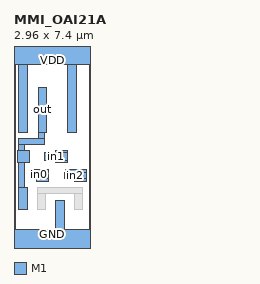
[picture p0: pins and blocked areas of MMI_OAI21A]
MACRO MMI_OAI21A
	CLASS CORE ;
	FOREIGN MMI_OAI21A 0 0 ;
	SIZE 2.96 BY 7.4 ;
	SYMMETRY X Y ;
	SITE CORE1 ;
	PIN out
		DIRECTION output ;
		USE SIGNAL ;
		PORT
			LAYER M1 ;
			RECT 0.94 4.275 1.28 6.035 ;
			LAYER M1 ;
			RECT 0.94 4.02 1.17 4.275 ;
			LAYER M1 ;
			RECT 0.18 3.79 1.17 4.02 ;
			LAYER M1 ;
			RECT 0.18 3.555 0.41 3.79 ;
			LAYER M1 ;
			RECT 0.145 3.105 0.595 3.555 ;
			LAYER M1 ;
			RECT 0.18 2.11 0.41 3.105 ;
			LAYER M1 ;
			RECT 0.18 1.27 0.52 2.11 ;
		END
		AntennaDiffArea 1.4168 ;
	END out
	PIN in1
		DIRECTION input ;
		USE SIGNAL ;
		PORT
			LAYER M1 ;
			RECT 1.625 3.5 2.075 3.555 ;
			LAYER M1 ;
			RECT 1.175 3.16 2.075 3.5 ;
			LAYER M1 ;
			RECT 1.625 3.105 2.075 3.16 ;
		END
		AntennaGateArea 0.4968 ;
	END in1
	PIN GND
		DIRECTION inout ;
		USE GROUND ;
		PORT
			LAYER M1 ;
			RECT 1.62 0.5 1.96 1.61 ;
			LAYER M1 ;
			RECT 0 -0.5 2.96 0.5 ;
		END
	END GND
	PIN in2
		DIRECTION input ;
		USE SIGNAL ;
		PORT
			LAYER M1 ;
			RECT 2.365 2.81 2.815 2.815 ;
			LAYER M1 ;
			RECT 2.025 2.695 2.815 2.81 ;
			LAYER M1 ;
			RECT 1.975 2.465 2.815 2.695 ;
			LAYER M1 ;
			RECT 2.365 2.365 2.815 2.465 ;
		END
		AntennaGateArea 0.4968 ;
	END in2
	PIN VDD
		DIRECTION inout ;
		USE POWER ;
		PORT
			LAYER M1 ;
			RECT 0 6.9 2.96 7.9 ;
			LAYER M1 ;
			RECT 0.18 4.275 0.52 6.9 ;
			LAYER M1 ;
			RECT 2.09 4.275 2.43 6.9 ;
		END
	END VDD
	PIN in0
		DIRECTION input ;
		USE SIGNAL ;
		PORT
			LAYER M1 ;
			RECT 0.885 2.81 1.335 2.815 ;
			LAYER M1 ;
			RECT 0.64 2.47 1.335 2.81 ;
			LAYER M1 ;
			RECT 0.885 2.365 1.335 2.47 ;
		END
		AntennaGateArea 0.3312 ;
	END in0
	OBS
		LAYER M1 ;
		RECT 0.9 1.88 2.68 2.11 ;
		LAYER M1 ;
		RECT 0.9 1.27 1.24 1.88 ;
		LAYER M1 ;
		RECT 2.34 1.27 2.68 1.88 ;
	END
END MMI_OAI21A
